VERSION 5.8 ;
BUSBITCHARS "[]" ;
DIVIDERCHAR "/" ;
UNITS
    DATABASE MICRONS 1000 ;
END UNITS

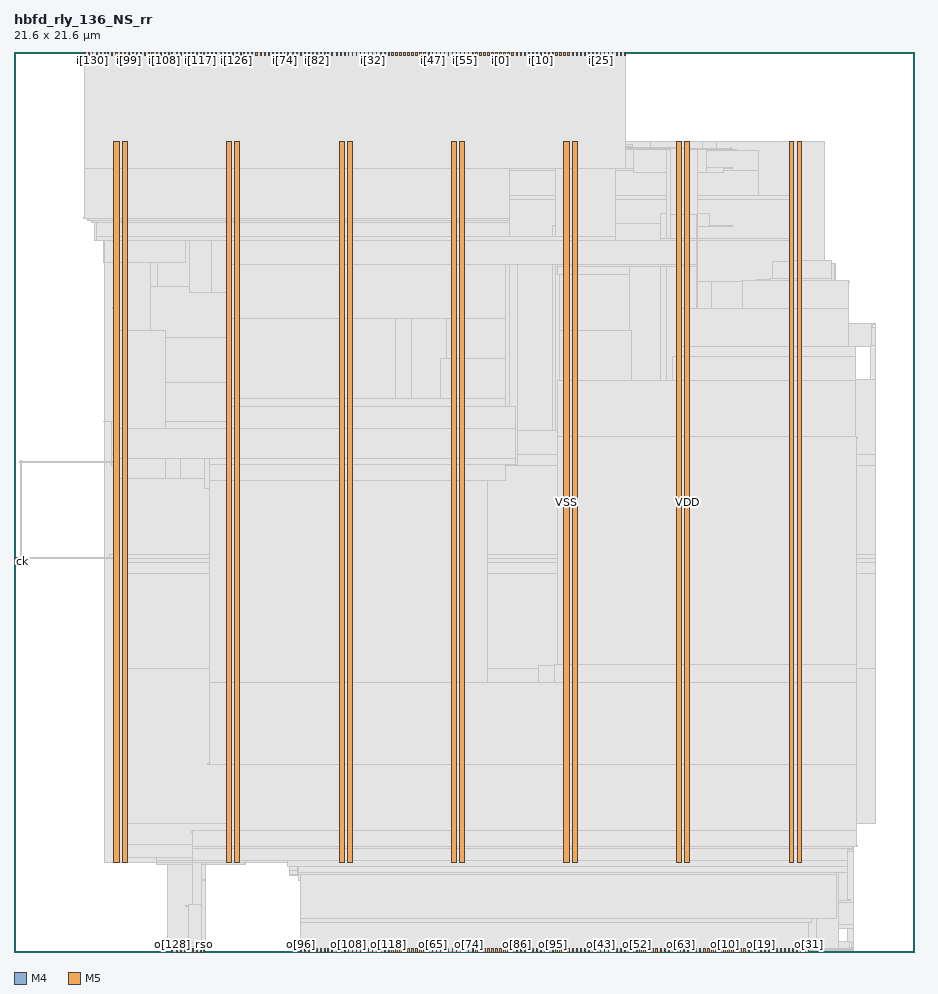
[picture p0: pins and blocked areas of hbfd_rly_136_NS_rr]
MACRO hbfd_rly_136_NS_rr
  FOREIGN hbfd_rly_136_NS_rr 0 0 ;
  CLASS BLOCK ;
  SIZE 21.6 BY 21.6 ;
  PIN ck
    DIRECTION INPUT ;
    USE SIGNAL ;
    PORT
      LAYER M4 ;
        RECT  0 9.36 0.084 9.384 ;
    END
  END ck
  PIN i[0]
    DIRECTION INPUT ;
    USE SIGNAL ;
    PORT
      LAYER M5 ;
        RECT  11.664 21.516 11.688 21.6 ;
    END
  END i[0]
  PIN i[100]
    DIRECTION INPUT ;
    USE SIGNAL ;
    PORT
      LAYER M5 ;
        RECT  2.832 21.516 2.856 21.6 ;
    END
  END i[100]
  PIN i[101]
    DIRECTION INPUT ;
    USE SIGNAL ;
    PORT
      LAYER M5 ;
        RECT  2.928 21.516 2.952 21.6 ;
    END
  END i[101]
  PIN i[102]
    DIRECTION INPUT ;
    USE SIGNAL ;
    PORT
      LAYER M5 ;
        RECT  3.024 21.516 3.048 21.6 ;
    END
  END i[102]
  PIN i[103]
    DIRECTION INPUT ;
    USE SIGNAL ;
    PORT
      LAYER M5 ;
        RECT  3.12 21.516 3.144 21.6 ;
    END
  END i[103]
  PIN i[104]
    DIRECTION INPUT ;
    USE SIGNAL ;
    PORT
      LAYER M5 ;
        RECT  3.216 21.516 3.24 21.6 ;
    END
  END i[104]
  PIN i[105]
    DIRECTION INPUT ;
    USE SIGNAL ;
    PORT
      LAYER M5 ;
        RECT  3.312 21.516 3.336 21.6 ;
    END
  END i[105]
  PIN i[106]
    DIRECTION INPUT ;
    USE SIGNAL ;
    PORT
      LAYER M5 ;
        RECT  3.408 21.516 3.432 21.6 ;
    END
  END i[106]
  PIN i[107]
    DIRECTION INPUT ;
    USE SIGNAL ;
    PORT
      LAYER M5 ;
        RECT  3.504 21.516 3.528 21.6 ;
    END
  END i[107]
  PIN i[108]
    DIRECTION INPUT ;
    USE SIGNAL ;
    PORT
      LAYER M5 ;
        RECT  3.6 21.516 3.624 21.6 ;
    END
  END i[108]
  PIN i[109]
    DIRECTION INPUT ;
    USE SIGNAL ;
    PORT
      LAYER M5 ;
        RECT  3.696 21.516 3.72 21.6 ;
    END
  END i[109]
  PIN i[10]
    DIRECTION INPUT ;
    USE SIGNAL ;
    PORT
      LAYER M5 ;
        RECT  12.624 21.516 12.648 21.6 ;
    END
  END i[10]
  PIN i[110]
    DIRECTION INPUT ;
    USE SIGNAL ;
    PORT
      LAYER M5 ;
        RECT  3.792 21.516 3.816 21.6 ;
    END
  END i[110]
  PIN i[111]
    DIRECTION INPUT ;
    USE SIGNAL ;
    PORT
      LAYER M5 ;
        RECT  3.888 21.516 3.912 21.6 ;
    END
  END i[111]
  PIN i[112]
    DIRECTION INPUT ;
    USE SIGNAL ;
    PORT
      LAYER M5 ;
        RECT  3.984 21.516 4.008 21.6 ;
    END
  END i[112]
  PIN i[113]
    DIRECTION INPUT ;
    USE SIGNAL ;
    PORT
      LAYER M5 ;
        RECT  4.08 21.516 4.104 21.6 ;
    END
  END i[113]
  PIN i[114]
    DIRECTION INPUT ;
    USE SIGNAL ;
    PORT
      LAYER M5 ;
        RECT  4.176 21.516 4.2 21.6 ;
    END
  END i[114]
  PIN i[115]
    DIRECTION INPUT ;
    USE SIGNAL ;
    PORT
      LAYER M5 ;
        RECT  4.272 21.516 4.296 21.6 ;
    END
  END i[115]
  PIN i[116]
    DIRECTION INPUT ;
    USE SIGNAL ;
    PORT
      LAYER M5 ;
        RECT  4.368 21.516 4.392 21.6 ;
    END
  END i[116]
  PIN i[117]
    DIRECTION INPUT ;
    USE SIGNAL ;
    PORT
      LAYER M5 ;
        RECT  4.464 21.516 4.488 21.6 ;
    END
  END i[117]
  PIN i[118]
    DIRECTION INPUT ;
    USE SIGNAL ;
    PORT
      LAYER M5 ;
        RECT  4.56 21.516 4.584 21.6 ;
    END
  END i[118]
  PIN i[119]
    DIRECTION INPUT ;
    USE SIGNAL ;
    PORT
      LAYER M5 ;
        RECT  4.656 21.516 4.68 21.6 ;
    END
  END i[119]
  PIN i[11]
    DIRECTION INPUT ;
    USE SIGNAL ;
    PORT
      LAYER M5 ;
        RECT  12.72 21.516 12.744 21.6 ;
    END
  END i[11]
  PIN i[120]
    DIRECTION INPUT ;
    USE SIGNAL ;
    PORT
      LAYER M5 ;
        RECT  4.752 21.516 4.776 21.6 ;
    END
  END i[120]
  PIN i[121]
    DIRECTION INPUT ;
    USE SIGNAL ;
    PORT
      LAYER M5 ;
        RECT  4.848 21.516 4.872 21.6 ;
    END
  END i[121]
  PIN i[122]
    DIRECTION INPUT ;
    USE SIGNAL ;
    PORT
      LAYER M5 ;
        RECT  4.944 21.516 4.968 21.6 ;
    END
  END i[122]
  PIN i[123]
    DIRECTION INPUT ;
    USE SIGNAL ;
    PORT
      LAYER M5 ;
        RECT  5.04 21.516 5.064 21.6 ;
    END
  END i[123]
  PIN i[124]
    DIRECTION INPUT ;
    USE SIGNAL ;
    PORT
      LAYER M5 ;
        RECT  5.136 21.516 5.16 21.6 ;
    END
  END i[124]
  PIN i[125]
    DIRECTION INPUT ;
    USE SIGNAL ;
    PORT
      LAYER M5 ;
        RECT  5.232 21.516 5.256 21.6 ;
    END
  END i[125]
  PIN i[126]
    DIRECTION INPUT ;
    USE SIGNAL ;
    PORT
      LAYER M5 ;
        RECT  5.328 21.516 5.352 21.6 ;
    END
  END i[126]
  PIN i[127]
    DIRECTION INPUT ;
    USE SIGNAL ;
    PORT
      LAYER M5 ;
        RECT  5.424 21.516 5.448 21.6 ;
    END
  END i[127]
  PIN i[128]
    DIRECTION INPUT ;
    USE SIGNAL ;
    PORT
      LAYER M5 ;
        RECT  1.68 21.516 1.704 21.6 ;
    END
  END i[128]
  PIN i[129]
    DIRECTION INPUT ;
    USE SIGNAL ;
    PORT
      LAYER M5 ;
        RECT  1.776 21.516 1.8 21.6 ;
    END
  END i[129]
  PIN i[12]
    DIRECTION INPUT ;
    USE SIGNAL ;
    PORT
      LAYER M5 ;
        RECT  12.816 21.516 12.84 21.6 ;
    END
  END i[12]
  PIN i[130]
    DIRECTION INPUT ;
    USE SIGNAL ;
    PORT
      LAYER M5 ;
        RECT  1.872 21.516 1.896 21.6 ;
    END
  END i[130]
  PIN i[131]
    DIRECTION INPUT ;
    USE SIGNAL ;
    PORT
      LAYER M5 ;
        RECT  1.968 21.516 1.992 21.6 ;
    END
  END i[131]
  PIN i[132]
    DIRECTION INPUT ;
    USE SIGNAL ;
    PORT
      LAYER M5 ;
        RECT  2.064 21.516 2.088 21.6 ;
    END
  END i[132]
  PIN i[133]
    DIRECTION INPUT ;
    USE SIGNAL ;
    PORT
      LAYER M5 ;
        RECT  2.16 21.516 2.184 21.6 ;
    END
  END i[133]
  PIN i[134]
    DIRECTION INPUT ;
    USE SIGNAL ;
    PORT
      LAYER M5 ;
        RECT  2.256 21.516 2.28 21.6 ;
    END
  END i[134]
  PIN i[135]
    DIRECTION INPUT ;
    USE SIGNAL ;
    PORT
      LAYER M5 ;
        RECT  2.352 21.516 2.376 21.6 ;
    END
  END i[135]
  PIN i[13]
    DIRECTION INPUT ;
    USE SIGNAL ;
    PORT
      LAYER M5 ;
        RECT  12.912 21.516 12.936 21.6 ;
    END
  END i[13]
  PIN i[14]
    DIRECTION INPUT ;
    USE SIGNAL ;
    PORT
      LAYER M5 ;
        RECT  13.008 21.516 13.032 21.6 ;
    END
  END i[14]
  PIN i[15]
    DIRECTION INPUT ;
    USE SIGNAL ;
    PORT
      LAYER M5 ;
        RECT  13.104 21.516 13.128 21.6 ;
    END
  END i[15]
  PIN i[16]
    DIRECTION INPUT ;
    USE SIGNAL ;
    PORT
      LAYER M5 ;
        RECT  13.2 21.516 13.224 21.6 ;
    END
  END i[16]
  PIN i[17]
    DIRECTION INPUT ;
    USE SIGNAL ;
    PORT
      LAYER M5 ;
        RECT  13.296 21.516 13.32 21.6 ;
    END
  END i[17]
  PIN i[18]
    DIRECTION INPUT ;
    USE SIGNAL ;
    PORT
      LAYER M5 ;
        RECT  13.392 21.516 13.416 21.6 ;
    END
  END i[18]
  PIN i[19]
    DIRECTION INPUT ;
    USE SIGNAL ;
    PORT
      LAYER M5 ;
        RECT  13.488 21.516 13.512 21.6 ;
    END
  END i[19]
  PIN i[1]
    DIRECTION INPUT ;
    USE SIGNAL ;
    PORT
      LAYER M5 ;
        RECT  11.76 21.516 11.784 21.6 ;
    END
  END i[1]
  PIN i[20]
    DIRECTION INPUT ;
    USE SIGNAL ;
    PORT
      LAYER M5 ;
        RECT  13.584 21.516 13.608 21.6 ;
    END
  END i[20]
  PIN i[21]
    DIRECTION INPUT ;
    USE SIGNAL ;
    PORT
      LAYER M5 ;
        RECT  13.68 21.516 13.704 21.6 ;
    END
  END i[21]
  PIN i[22]
    DIRECTION INPUT ;
    USE SIGNAL ;
    PORT
      LAYER M5 ;
        RECT  13.776 21.516 13.8 21.6 ;
    END
  END i[22]
  PIN i[23]
    DIRECTION INPUT ;
    USE SIGNAL ;
    PORT
      LAYER M5 ;
        RECT  13.872 21.516 13.896 21.6 ;
    END
  END i[23]
  PIN i[24]
    DIRECTION INPUT ;
    USE SIGNAL ;
    PORT
      LAYER M5 ;
        RECT  13.968 21.516 13.992 21.6 ;
    END
  END i[24]
  PIN i[25]
    DIRECTION INPUT ;
    USE SIGNAL ;
    PORT
      LAYER M5 ;
        RECT  14.064 21.516 14.088 21.6 ;
    END
  END i[25]
  PIN i[26]
    DIRECTION INPUT ;
    USE SIGNAL ;
    PORT
      LAYER M5 ;
        RECT  14.16 21.516 14.184 21.6 ;
    END
  END i[26]
  PIN i[27]
    DIRECTION INPUT ;
    USE SIGNAL ;
    PORT
      LAYER M5 ;
        RECT  14.256 21.516 14.28 21.6 ;
    END
  END i[27]
  PIN i[28]
    DIRECTION INPUT ;
    USE SIGNAL ;
    PORT
      LAYER M5 ;
        RECT  14.352 21.516 14.376 21.6 ;
    END
  END i[28]
  PIN i[29]
    DIRECTION INPUT ;
    USE SIGNAL ;
    PORT
      LAYER M5 ;
        RECT  14.448 21.516 14.472 21.6 ;
    END
  END i[29]
  PIN i[2]
    DIRECTION INPUT ;
    USE SIGNAL ;
    PORT
      LAYER M5 ;
        RECT  11.856 21.516 11.88 21.6 ;
    END
  END i[2]
  PIN i[30]
    DIRECTION INPUT ;
    USE SIGNAL ;
    PORT
      LAYER M5 ;
        RECT  14.544 21.516 14.568 21.6 ;
    END
  END i[30]
  PIN i[31]
    DIRECTION INPUT ;
    USE SIGNAL ;
    PORT
      LAYER M5 ;
        RECT  14.64 21.516 14.664 21.6 ;
    END
  END i[31]
  PIN i[32]
    DIRECTION INPUT ;
    USE SIGNAL ;
    PORT
      LAYER M5 ;
        RECT  8.592 21.516 8.616 21.6 ;
    END
  END i[32]
  PIN i[33]
    DIRECTION INPUT ;
    USE SIGNAL ;
    PORT
      LAYER M5 ;
        RECT  8.688 21.516 8.712 21.6 ;
    END
  END i[33]
  PIN i[34]
    DIRECTION INPUT ;
    USE SIGNAL ;
    PORT
      LAYER M5 ;
        RECT  8.784 21.516 8.808 21.6 ;
    END
  END i[34]
  PIN i[35]
    DIRECTION INPUT ;
    USE SIGNAL ;
    PORT
      LAYER M5 ;
        RECT  8.88 21.516 8.904 21.6 ;
    END
  END i[35]
  PIN i[36]
    DIRECTION INPUT ;
    USE SIGNAL ;
    PORT
      LAYER M5 ;
        RECT  8.976 21.516 9 21.6 ;
    END
  END i[36]
  PIN i[37]
    DIRECTION INPUT ;
    USE SIGNAL ;
    PORT
      LAYER M5 ;
        RECT  9.072 21.516 9.096 21.6 ;
    END
  END i[37]
  PIN i[38]
    DIRECTION INPUT ;
    USE SIGNAL ;
    PORT
      LAYER M5 ;
        RECT  9.168 21.516 9.192 21.6 ;
    END
  END i[38]
  PIN i[39]
    DIRECTION INPUT ;
    USE SIGNAL ;
    PORT
      LAYER M5 ;
        RECT  9.264 21.516 9.288 21.6 ;
    END
  END i[39]
  PIN i[3]
    DIRECTION INPUT ;
    USE SIGNAL ;
    PORT
      LAYER M5 ;
        RECT  11.952 21.516 11.976 21.6 ;
    END
  END i[3]
  PIN i[40]
    DIRECTION INPUT ;
    USE SIGNAL ;
    PORT
      LAYER M5 ;
        RECT  9.36 21.516 9.384 21.6 ;
    END
  END i[40]
  PIN i[41]
    DIRECTION INPUT ;
    USE SIGNAL ;
    PORT
      LAYER M5 ;
        RECT  9.456 21.516 9.48 21.6 ;
    END
  END i[41]
  PIN i[42]
    DIRECTION INPUT ;
    USE SIGNAL ;
    PORT
      LAYER M5 ;
        RECT  9.552 21.516 9.576 21.6 ;
    END
  END i[42]
  PIN i[43]
    DIRECTION INPUT ;
    USE SIGNAL ;
    PORT
      LAYER M5 ;
        RECT  9.648 21.516 9.672 21.6 ;
    END
  END i[43]
  PIN i[44]
    DIRECTION INPUT ;
    USE SIGNAL ;
    PORT
      LAYER M5 ;
        RECT  9.744 21.516 9.768 21.6 ;
    END
  END i[44]
  PIN i[45]
    DIRECTION INPUT ;
    USE SIGNAL ;
    PORT
      LAYER M5 ;
        RECT  9.84 21.516 9.864 21.6 ;
    END
  END i[45]
  PIN i[46]
    DIRECTION INPUT ;
    USE SIGNAL ;
    PORT
      LAYER M5 ;
        RECT  9.936 21.516 9.96 21.6 ;
    END
  END i[46]
  PIN i[47]
    DIRECTION INPUT ;
    USE SIGNAL ;
    PORT
      LAYER M5 ;
        RECT  10.032 21.516 10.056 21.6 ;
    END
  END i[47]
  PIN i[48]
    DIRECTION INPUT ;
    USE SIGNAL ;
    PORT
      LAYER M5 ;
        RECT  10.128 21.516 10.152 21.6 ;
    END
  END i[48]
  PIN i[49]
    DIRECTION INPUT ;
    USE SIGNAL ;
    PORT
      LAYER M5 ;
        RECT  10.224 21.516 10.248 21.6 ;
    END
  END i[49]
  PIN i[4]
    DIRECTION INPUT ;
    USE SIGNAL ;
    PORT
      LAYER M5 ;
        RECT  12.048 21.516 12.072 21.6 ;
    END
  END i[4]
  PIN i[50]
    DIRECTION INPUT ;
    USE SIGNAL ;
    PORT
      LAYER M5 ;
        RECT  10.32 21.516 10.344 21.6 ;
    END
  END i[50]
  PIN i[51]
    DIRECTION INPUT ;
    USE SIGNAL ;
    PORT
      LAYER M5 ;
        RECT  10.416 21.516 10.44 21.6 ;
    END
  END i[51]
  PIN i[52]
    DIRECTION INPUT ;
    USE SIGNAL ;
    PORT
      LAYER M5 ;
        RECT  10.512 21.516 10.536 21.6 ;
    END
  END i[52]
  PIN i[53]
    DIRECTION INPUT ;
    USE SIGNAL ;
    PORT
      LAYER M5 ;
        RECT  10.608 21.516 10.632 21.6 ;
    END
  END i[53]
  PIN i[54]
    DIRECTION INPUT ;
    USE SIGNAL ;
    PORT
      LAYER M5 ;
        RECT  10.704 21.516 10.728 21.6 ;
    END
  END i[54]
  PIN i[55]
    DIRECTION INPUT ;
    USE SIGNAL ;
    PORT
      LAYER M5 ;
        RECT  10.8 21.516 10.824 21.6 ;
    END
  END i[55]
  PIN i[56]
    DIRECTION INPUT ;
    USE SIGNAL ;
    PORT
      LAYER M5 ;
        RECT  10.896 21.516 10.92 21.6 ;
    END
  END i[56]
  PIN i[57]
    DIRECTION INPUT ;
    USE SIGNAL ;
    PORT
      LAYER M5 ;
        RECT  10.992 21.516 11.016 21.6 ;
    END
  END i[57]
  PIN i[58]
    DIRECTION INPUT ;
    USE SIGNAL ;
    PORT
      LAYER M5 ;
        RECT  11.088 21.516 11.112 21.6 ;
    END
  END i[58]
  PIN i[59]
    DIRECTION INPUT ;
    USE SIGNAL ;
    PORT
      LAYER M5 ;
        RECT  11.184 21.516 11.208 21.6 ;
    END
  END i[59]
  PIN i[5]
    DIRECTION INPUT ;
    USE SIGNAL ;
    PORT
      LAYER M5 ;
        RECT  12.144 21.516 12.168 21.6 ;
    END
  END i[5]
  PIN i[60]
    DIRECTION INPUT ;
    USE SIGNAL ;
    PORT
      LAYER M5 ;
        RECT  11.28 21.516 11.304 21.6 ;
    END
  END i[60]
  PIN i[61]
    DIRECTION INPUT ;
    USE SIGNAL ;
    PORT
      LAYER M5 ;
        RECT  11.376 21.516 11.4 21.6 ;
    END
  END i[61]
  PIN i[62]
    DIRECTION INPUT ;
    USE SIGNAL ;
    PORT
      LAYER M5 ;
        RECT  11.472 21.516 11.496 21.6 ;
    END
  END i[62]
  PIN i[63]
    DIRECTION INPUT ;
    USE SIGNAL ;
    PORT
      LAYER M5 ;
        RECT  11.568 21.516 11.592 21.6 ;
    END
  END i[63]
  PIN i[64]
    DIRECTION INPUT ;
    USE SIGNAL ;
    PORT
      LAYER M5 ;
        RECT  5.52 21.516 5.544 21.6 ;
    END
  END i[64]
  PIN i[65]
    DIRECTION INPUT ;
    USE SIGNAL ;
    PORT
      LAYER M5 ;
        RECT  5.616 21.516 5.64 21.6 ;
    END
  END i[65]
  PIN i[66]
    DIRECTION INPUT ;
    USE SIGNAL ;
    PORT
      LAYER M5 ;
        RECT  5.712 21.516 5.736 21.6 ;
    END
  END i[66]
  PIN i[67]
    DIRECTION INPUT ;
    USE SIGNAL ;
    PORT
      LAYER M5 ;
        RECT  5.808 21.516 5.832 21.6 ;
    END
  END i[67]
  PIN i[68]
    DIRECTION INPUT ;
    USE SIGNAL ;
    PORT
      LAYER M5 ;
        RECT  5.904 21.516 5.928 21.6 ;
    END
  END i[68]
  PIN i[69]
    DIRECTION INPUT ;
    USE SIGNAL ;
    PORT
      LAYER M5 ;
        RECT  6 21.516 6.024 21.6 ;
    END
  END i[69]
  PIN i[6]
    DIRECTION INPUT ;
    USE SIGNAL ;
    PORT
      LAYER M5 ;
        RECT  12.24 21.516 12.264 21.6 ;
    END
  END i[6]
  PIN i[70]
    DIRECTION INPUT ;
    USE SIGNAL ;
    PORT
      LAYER M5 ;
        RECT  6.096 21.516 6.12 21.6 ;
    END
  END i[70]
  PIN i[71]
    DIRECTION INPUT ;
    USE SIGNAL ;
    PORT
      LAYER M5 ;
        RECT  6.192 21.516 6.216 21.6 ;
    END
  END i[71]
  PIN i[72]
    DIRECTION INPUT ;
    USE SIGNAL ;
    PORT
      LAYER M5 ;
        RECT  6.288 21.516 6.312 21.6 ;
    END
  END i[72]
  PIN i[73]
    DIRECTION INPUT ;
    USE SIGNAL ;
    PORT
      LAYER M5 ;
        RECT  6.384 21.516 6.408 21.6 ;
    END
  END i[73]
  PIN i[74]
    DIRECTION INPUT ;
    USE SIGNAL ;
    PORT
      LAYER M5 ;
        RECT  6.48 21.516 6.504 21.6 ;
    END
  END i[74]
  PIN i[75]
    DIRECTION INPUT ;
    USE SIGNAL ;
    PORT
      LAYER M5 ;
        RECT  6.576 21.516 6.6 21.6 ;
    END
  END i[75]
  PIN i[76]
    DIRECTION INPUT ;
    USE SIGNAL ;
    PORT
      LAYER M5 ;
        RECT  6.672 21.516 6.696 21.6 ;
    END
  END i[76]
  PIN i[77]
    DIRECTION INPUT ;
    USE SIGNAL ;
    PORT
      LAYER M5 ;
        RECT  6.768 21.516 6.792 21.6 ;
    END
  END i[77]
  PIN i[78]
    DIRECTION INPUT ;
    USE SIGNAL ;
    PORT
      LAYER M5 ;
        RECT  6.864 21.516 6.888 21.6 ;
    END
  END i[78]
  PIN i[79]
    DIRECTION INPUT ;
    USE SIGNAL ;
    PORT
      LAYER M5 ;
        RECT  6.96 21.516 6.984 21.6 ;
    END
  END i[79]
  PIN i[7]
    DIRECTION INPUT ;
    USE SIGNAL ;
    PORT
      LAYER M5 ;
        RECT  12.336 21.516 12.36 21.6 ;
    END
  END i[7]
  PIN i[80]
    DIRECTION INPUT ;
    USE SIGNAL ;
    PORT
      LAYER M5 ;
        RECT  7.056 21.516 7.08 21.6 ;
    END
  END i[80]
  PIN i[81]
    DIRECTION INPUT ;
    USE SIGNAL ;
    PORT
      LAYER M5 ;
        RECT  7.152 21.516 7.176 21.6 ;
    END
  END i[81]
  PIN i[82]
    DIRECTION INPUT ;
    USE SIGNAL ;
    PORT
      LAYER M5 ;
        RECT  7.248 21.516 7.272 21.6 ;
    END
  END i[82]
  PIN i[83]
    DIRECTION INPUT ;
    USE SIGNAL ;
    PORT
      LAYER M5 ;
        RECT  7.344 21.516 7.368 21.6 ;
    END
  END i[83]
  PIN i[84]
    DIRECTION INPUT ;
    USE SIGNAL ;
    PORT
      LAYER M5 ;
        RECT  7.44 21.516 7.464 21.6 ;
    END
  END i[84]
  PIN i[85]
    DIRECTION INPUT ;
    USE SIGNAL ;
    PORT
      LAYER M5 ;
        RECT  7.536 21.516 7.56 21.6 ;
    END
  END i[85]
  PIN i[86]
    DIRECTION INPUT ;
    USE SIGNAL ;
    PORT
      LAYER M5 ;
        RECT  7.632 21.516 7.656 21.6 ;
    END
  END i[86]
  PIN i[87]
    DIRECTION INPUT ;
    USE SIGNAL ;
    PORT
      LAYER M5 ;
        RECT  7.728 21.516 7.752 21.6 ;
    END
  END i[87]
  PIN i[88]
    DIRECTION INPUT ;
    USE SIGNAL ;
    PORT
      LAYER M5 ;
        RECT  7.824 21.516 7.848 21.6 ;
    END
  END i[88]
  PIN i[89]
    DIRECTION INPUT ;
    USE SIGNAL ;
    PORT
      LAYER M5 ;
        RECT  7.92 21.516 7.944 21.6 ;
    END
  END i[89]
  PIN i[8]
    DIRECTION INPUT ;
    USE SIGNAL ;
    PORT
      LAYER M5 ;
        RECT  12.432 21.516 12.456 21.6 ;
    END
  END i[8]
  PIN i[90]
    DIRECTION INPUT ;
    USE SIGNAL ;
    PORT
      LAYER M5 ;
        RECT  8.016 21.516 8.04 21.6 ;
    END
  END i[90]
  PIN i[91]
    DIRECTION INPUT ;
    USE SIGNAL ;
    PORT
      LAYER M5 ;
        RECT  8.112 21.516 8.136 21.6 ;
    END
  END i[91]
  PIN i[92]
    DIRECTION INPUT ;
    USE SIGNAL ;
    PORT
      LAYER M5 ;
        RECT  8.208 21.516 8.232 21.6 ;
    END
  END i[92]
  PIN i[93]
    DIRECTION INPUT ;
    USE SIGNAL ;
    PORT
      LAYER M5 ;
        RECT  8.304 21.516 8.328 21.6 ;
    END
  END i[93]
  PIN i[94]
    DIRECTION INPUT ;
    USE SIGNAL ;
    PORT
      LAYER M5 ;
        RECT  8.4 21.516 8.424 21.6 ;
    END
  END i[94]
  PIN i[95]
    DIRECTION INPUT ;
    USE SIGNAL ;
    PORT
      LAYER M5 ;
        RECT  8.496 21.516 8.52 21.6 ;
    END
  END i[95]
  PIN i[96]
    DIRECTION INPUT ;
    USE SIGNAL ;
    PORT
      LAYER M5 ;
        RECT  2.448 21.516 2.472 21.6 ;
    END
  END i[96]
  PIN i[97]
    DIRECTION INPUT ;
    USE SIGNAL ;
    PORT
      LAYER M5 ;
        RECT  2.544 21.516 2.568 21.6 ;
    END
  END i[97]
  PIN i[98]
    DIRECTION INPUT ;
    USE SIGNAL ;
    PORT
      LAYER M5 ;
        RECT  2.64 21.516 2.664 21.6 ;
    END
  END i[98]
  PIN i[99]
    DIRECTION INPUT ;
    USE SIGNAL ;
    PORT
      LAYER M5 ;
        RECT  2.736 21.516 2.76 21.6 ;
    END
  END i[99]
  PIN i[9]
    DIRECTION INPUT ;
    USE SIGNAL ;
    PORT
      LAYER M5 ;
        RECT  12.528 21.516 12.552 21.6 ;
    END
  END i[9]
  PIN o[0]
    DIRECTION OUTPUT ;
    USE SIGNAL ;
    PORT
      LAYER M5 ;
        RECT  16.08 0 16.104 0.084 ;
    END
  END o[0]
  PIN o[100]
    DIRECTION OUTPUT ;
    USE SIGNAL ;
    PORT
      LAYER M5 ;
        RECT  7.248 0 7.272 0.084 ;
    END
  END o[100]
  PIN o[101]
    DIRECTION OUTPUT ;
    USE SIGNAL ;
    PORT
      LAYER M5 ;
        RECT  7.344 0 7.368 0.084 ;
    END
  END o[101]
  PIN o[102]
    DIRECTION OUTPUT ;
    USE SIGNAL ;
    PORT
      LAYER M5 ;
        RECT  7.44 0 7.464 0.084 ;
    END
  END o[102]
  PIN o[103]
    DIRECTION OUTPUT ;
    USE SIGNAL ;
    PORT
      LAYER M5 ;
        RECT  7.536 0 7.56 0.084 ;
    END
  END o[103]
  PIN o[104]
    DIRECTION OUTPUT ;
    USE SIGNAL ;
    PORT
      LAYER M5 ;
        RECT  7.632 0 7.656 0.084 ;
    END
  END o[104]
  PIN o[105]
    DIRECTION OUTPUT ;
    USE SIGNAL ;
    PORT
      LAYER M5 ;
        RECT  7.728 0 7.752 0.084 ;
    END
  END o[105]
  PIN o[106]
    DIRECTION OUTPUT ;
    USE SIGNAL ;
    PORT
      LAYER M5 ;
        RECT  7.824 0 7.848 0.084 ;
    END
  END o[106]
  PIN o[107]
    DIRECTION OUTPUT ;
    USE SIGNAL ;
    PORT
      LAYER M5 ;
        RECT  7.92 0 7.944 0.084 ;
    END
  END o[107]
  PIN o[108]
    DIRECTION OUTPUT ;
    USE SIGNAL ;
    PORT
      LAYER M5 ;
        RECT  8.016 0 8.04 0.084 ;
    END
  END o[108]
  PIN o[109]
    DIRECTION OUTPUT ;
    USE SIGNAL ;
    PORT
      LAYER M5 ;
        RECT  8.112 0 8.136 0.084 ;
    END
  END o[109]
  PIN o[10]
    DIRECTION OUTPUT ;
    USE SIGNAL ;
    PORT
      LAYER M5 ;
        RECT  17.04 0 17.064 0.084 ;
    END
  END o[10]
  PIN o[110]
    DIRECTION OUTPUT ;
    USE SIGNAL ;
    PORT
      LAYER M5 ;
        RECT  8.208 0 8.232 0.084 ;
    END
  END o[110]
  PIN o[111]
    DIRECTION OUTPUT ;
    USE SIGNAL ;
    PORT
      LAYER M5 ;
        RECT  8.304 0 8.328 0.084 ;
    END
  END o[111]
  PIN o[112]
    DIRECTION OUTPUT ;
    USE SIGNAL ;
    PORT
      LAYER M5 ;
        RECT  8.4 0 8.424 0.084 ;
    END
  END o[112]
  PIN o[113]
    DIRECTION OUTPUT ;
    USE SIGNAL ;
    PORT
      LAYER M5 ;
        RECT  8.496 0 8.52 0.084 ;
    END
  END o[113]
  PIN o[114]
    DIRECTION OUTPUT ;
    USE SIGNAL ;
    PORT
      LAYER M5 ;
        RECT  8.592 0 8.616 0.084 ;
    END
  END o[114]
  PIN o[115]
    DIRECTION OUTPUT ;
    USE SIGNAL ;
    PORT
      LAYER M5 ;
        RECT  8.688 0 8.712 0.084 ;
    END
  END o[115]
  PIN o[116]
    DIRECTION OUTPUT ;
    USE SIGNAL ;
    PORT
      LAYER M5 ;
        RECT  8.784 0 8.808 0.084 ;
    END
  END o[116]
  PIN o[117]
    DIRECTION OUTPUT ;
    USE SIGNAL ;
    PORT
      LAYER M5 ;
        RECT  8.88 0 8.904 0.084 ;
    END
  END o[117]
  PIN o[118]
    DIRECTION OUTPUT ;
    USE SIGNAL ;
    PORT
      LAYER M5 ;
        RECT  8.976 0 9 0.084 ;
    END
  END o[118]
  PIN o[119]
    DIRECTION OUTPUT ;
    USE SIGNAL ;
    PORT
      LAYER M5 ;
        RECT  9.072 0 9.096 0.084 ;
    END
  END o[119]
  PIN o[11]
    DIRECTION OUTPUT ;
    USE SIGNAL ;
    PORT
      LAYER M5 ;
        RECT  17.136 0 17.16 0.084 ;
    END
  END o[11]
  PIN o[120]
    DIRECTION OUTPUT ;
    USE SIGNAL ;
    PORT
      LAYER M5 ;
        RECT  9.168 0 9.192 0.084 ;
    END
  END o[120]
  PIN o[121]
    DIRECTION OUTPUT ;
    USE SIGNAL ;
    PORT
      LAYER M5 ;
        RECT  9.264 0 9.288 0.084 ;
    END
  END o[121]
  PIN o[122]
    DIRECTION OUTPUT ;
    USE SIGNAL ;
    PORT
      LAYER M5 ;
        RECT  9.36 0 9.384 0.084 ;
    END
  END o[122]
  PIN o[123]
    DIRECTION OUTPUT ;
    USE SIGNAL ;
    PORT
      LAYER M5 ;
        RECT  9.456 0 9.48 0.084 ;
    END
  END o[123]
  PIN o[124]
    DIRECTION OUTPUT ;
    USE SIGNAL ;
    PORT
      LAYER M5 ;
        RECT  9.552 0 9.576 0.084 ;
    END
  END o[124]
  PIN o[125]
    DIRECTION OUTPUT ;
    USE SIGNAL ;
    PORT
      LAYER M5 ;
        RECT  9.648 0 9.672 0.084 ;
    END
  END o[125]
  PIN o[126]
    DIRECTION OUTPUT ;
    USE SIGNAL ;
    PORT
      LAYER M5 ;
        RECT  9.744 0 9.768 0.084 ;
    END
  END o[126]
  PIN o[127]
    DIRECTION OUTPUT ;
    USE SIGNAL ;
    PORT
      LAYER M5 ;
        RECT  9.84 0 9.864 0.084 ;
    END
  END o[127]
  PIN o[128]
    DIRECTION OUTPUT ;
    USE SIGNAL ;
    PORT
      LAYER M5 ;
        RECT  3.792 0 3.816 0.084 ;
    END
  END o[128]
  PIN o[129]
    DIRECTION OUTPUT ;
    USE SIGNAL ;
    PORT
      LAYER M5 ;
        RECT  3.888 0 3.912 0.084 ;
    END
  END o[129]
  PIN o[12]
    DIRECTION OUTPUT ;
    USE SIGNAL ;
    PORT
      LAYER M5 ;
        RECT  17.232 0 17.256 0.084 ;
    END
  END o[12]
  PIN o[130]
    DIRECTION OUTPUT ;
    USE SIGNAL ;
    PORT
      LAYER M5 ;
        RECT  3.984 0 4.008 0.084 ;
    END
  END o[130]
  PIN o[131]
    DIRECTION OUTPUT ;
    USE SIGNAL ;
    PORT
      LAYER M5 ;
        RECT  4.08 0 4.104 0.084 ;
    END
  END o[131]
  PIN o[132]
    DIRECTION OUTPUT ;
    USE SIGNAL ;
    PORT
      LAYER M5 ;
        RECT  4.176 0 4.2 0.084 ;
    END
  END o[132]
  PIN o[133]
    DIRECTION OUTPUT ;
    USE SIGNAL ;
    PORT
      LAYER M5 ;
        RECT  4.272 0 4.296 0.084 ;
    END
  END o[133]
  PIN o[134]
    DIRECTION OUTPUT ;
    USE SIGNAL ;
    PORT
      LAYER M5 ;
        RECT  4.368 0 4.392 0.084 ;
    END
  END o[134]
  PIN o[135]
    DIRECTION OUTPUT ;
    USE SIGNAL ;
    PORT
      LAYER M5 ;
        RECT  4.464 0 4.488 0.084 ;
    END
  END o[135]
  PIN o[13]
    DIRECTION OUTPUT ;
    USE SIGNAL ;
    PORT
      LAYER M5 ;
        RECT  17.328 0 17.352 0.084 ;
    END
  END o[13]
  PIN o[14]
    DIRECTION OUTPUT ;
    USE SIGNAL ;
    PORT
      LAYER M5 ;
        RECT  17.424 0 17.448 0.084 ;
    END
  END o[14]
  PIN o[15]
    DIRECTION OUTPUT ;
    USE SIGNAL ;
    PORT
      LAYER M5 ;
        RECT  17.52 0 17.544 0.084 ;
    END
  END o[15]
  PIN o[16]
    DIRECTION OUTPUT ;
    USE SIGNAL ;
    PORT
      LAYER M5 ;
        RECT  17.616 0 17.64 0.084 ;
    END
  END o[16]
  PIN o[17]
    DIRECTION OUTPUT ;
    USE SIGNAL ;
    PORT
      LAYER M5 ;
        RECT  17.712 0 17.736 0.084 ;
    END
  END o[17]
  PIN o[18]
    DIRECTION OUTPUT ;
    USE SIGNAL ;
    PORT
      LAYER M5 ;
        RECT  17.808 0 17.832 0.084 ;
    END
  END o[18]
  PIN o[19]
    DIRECTION OUTPUT ;
    USE SIGNAL ;
    PORT
      LAYER M5 ;
        RECT  17.904 0 17.928 0.084 ;
    END
  END o[19]
  PIN o[1]
    DIRECTION OUTPUT ;
    USE SIGNAL ;
    PORT
      LAYER M5 ;
        RECT  16.176 0 16.2 0.084 ;
    END
  END o[1]
  PIN o[20]
    DIRECTION OUTPUT ;
    USE SIGNAL ;
    PORT
      LAYER M5 ;
        RECT  18 0 18.024 0.084 ;
    END
  END o[20]
  PIN o[21]
    DIRECTION OUTPUT ;
    USE SIGNAL ;
    PORT
      LAYER M5 ;
        RECT  18.096 0 18.12 0.084 ;
    END
  END o[21]
  PIN o[22]
    DIRECTION OUTPUT ;
    USE SIGNAL ;
    PORT
      LAYER M5 ;
        RECT  18.192 0 18.216 0.084 ;
    END
  END o[22]
  PIN o[23]
    DIRECTION OUTPUT ;
    USE SIGNAL ;
    PORT
      LAYER M5 ;
        RECT  18.288 0 18.312 0.084 ;
    END
  END o[23]
  PIN o[24]
    DIRECTION OUTPUT ;
    USE SIGNAL ;
    PORT
      LAYER M5 ;
        RECT  18.384 0 18.408 0.084 ;
    END
  END o[24]
  PIN o[25]
    DIRECTION OUTPUT ;
    USE SIGNAL ;
    PORT
      LAYER M5 ;
        RECT  18.48 0 18.504 0.084 ;
    END
  END o[25]
  PIN o[26]
    DIRECTION OUTPUT ;
    USE SIGNAL ;
    PORT
      LAYER M5 ;
        RECT  18.576 0 18.6 0.084 ;
    END
  END o[26]
  PIN o[27]
    DIRECTION OUTPUT ;
    USE SIGNAL ;
    PORT
      LAYER M5 ;
        RECT  18.672 0 18.696 0.084 ;
    END
  END o[27]
  PIN o[28]
    DIRECTION OUTPUT ;
    USE SIGNAL ;
    PORT
      LAYER M5 ;
        RECT  18.768 0 18.792 0.084 ;
    END
  END o[28]
  PIN o[29]
    DIRECTION OUTPUT ;
    USE SIGNAL ;
    PORT
      LAYER M5 ;
        RECT  18.864 0 18.888 0.084 ;
    END
  END o[29]
  PIN o[2]
    DIRECTION OUTPUT ;
    USE SIGNAL ;
    PORT
      LAYER M5 ;
        RECT  16.272 0 16.296 0.084 ;
    END
  END o[2]
  PIN o[30]
    DIRECTION OUTPUT ;
    USE SIGNAL ;
    PORT
      LAYER M5 ;
        RECT  18.96 0 18.984 0.084 ;
    END
  END o[30]
  PIN o[31]
    DIRECTION OUTPUT ;
    USE SIGNAL ;
    PORT
      LAYER M5 ;
        RECT  19.056 0 19.08 0.084 ;
    END
  END o[31]
  PIN o[32]
    DIRECTION OUTPUT ;
    USE SIGNAL ;
    PORT
      LAYER M5 ;
        RECT  13.008 0 13.032 0.084 ;
    END
  END o[32]
  PIN o[33]
    DIRECTION OUTPUT ;
    USE SIGNAL ;
    PORT
      LAYER M5 ;
        RECT  13.104 0 13.128 0.084 ;
    END
  END o[33]
  PIN o[34]
    DIRECTION OUTPUT ;
    USE SIGNAL ;
    PORT
      LAYER M5 ;
        RECT  13.2 0 13.224 0.084 ;
    END
  END o[34]
  PIN o[35]
    DIRECTION OUTPUT ;
    USE SIGNAL ;
    PORT
      LAYER M5 ;
        RECT  13.296 0 13.32 0.084 ;
    END
  END o[35]
  PIN o[36]
    DIRECTION OUTPUT ;
    USE SIGNAL ;
    PORT
      LAYER M5 ;
        RECT  13.392 0 13.416 0.084 ;
    END
  END o[36]
  PIN o[37]
    DIRECTION OUTPUT ;
    USE SIGNAL ;
    PORT
      LAYER M5 ;
        RECT  13.488 0 13.512 0.084 ;
    END
  END o[37]
  PIN o[38]
    DIRECTION OUTPUT ;
    USE SIGNAL ;
    PORT
      LAYER M5 ;
        RECT  13.584 0 13.608 0.084 ;
    END
  END o[38]
  PIN o[39]
    DIRECTION OUTPUT ;
    USE SIGNAL ;
    PORT
      LAYER M5 ;
        RECT  13.68 0 13.704 0.084 ;
    END
  END o[39]
  PIN o[3]
    DIRECTION OUTPUT ;
    USE SIGNAL ;
    PORT
      LAYER M5 ;
        RECT  16.368 0 16.392 0.084 ;
    END
  END o[3]
  PIN o[40]
    DIRECTION OUTPUT ;
    USE SIGNAL ;
    PORT
      LAYER M5 ;
        RECT  13.776 0 13.8 0.084 ;
    END
  END o[40]
  PIN o[41]
    DIRECTION OUTPUT ;
    USE SIGNAL ;
    PORT
      LAYER M5 ;
        RECT  13.872 0 13.896 0.084 ;
    END
  END o[41]
  PIN o[42]
    DIRECTION OUTPUT ;
    USE SIGNAL ;
    PORT
      LAYER M5 ;
        RECT  13.968 0 13.992 0.084 ;
    END
  END o[42]
  PIN o[43]
    DIRECTION OUTPUT ;
    USE SIGNAL ;
    PORT
      LAYER M5 ;
        RECT  14.064 0 14.088 0.084 ;
    END
  END o[43]
  PIN o[44]
    DIRECTION OUTPUT ;
    USE SIGNAL ;
    PORT
      LAYER M5 ;
        RECT  14.16 0 14.184 0.084 ;
    END
  END o[44]
  PIN o[45]
    DIRECTION OUTPUT ;
    USE SIGNAL ;
    PORT
      LAYER M5 ;
        RECT  14.256 0 14.28 0.084 ;
    END
  END o[45]
  PIN o[46]
    DIRECTION OUTPUT ;
    USE SIGNAL ;
    PORT
      LAYER M5 ;
        RECT  14.352 0 14.376 0.084 ;
    END
  END o[46]
  PIN o[47]
    DIRECTION OUTPUT ;
    USE SIGNAL ;
    PORT
      LAYER M5 ;
        RECT  14.448 0 14.472 0.084 ;
    END
  END o[47]
  PIN o[48]
    DIRECTION OUTPUT ;
    USE SIGNAL ;
    PORT
      LAYER M5 ;
        RECT  14.544 0 14.568 0.084 ;
    END
  END o[48]
  PIN o[49]
    DIRECTION OUTPUT ;
    USE SIGNAL ;
    PORT
      LAYER M5 ;
        RECT  14.64 0 14.664 0.084 ;
    END
  END o[49]
  PIN o[4]
    DIRECTION OUTPUT ;
    USE SIGNAL ;
    PORT
      LAYER M5 ;
        RECT  16.464 0 16.488 0.084 ;
    END
  END o[4]
  PIN o[50]
    DIRECTION OUTPUT ;
    USE SIGNAL ;
    PORT
      LAYER M5 ;
        RECT  14.736 0 14.76 0.084 ;
    END
  END o[50]
  PIN o[51]
    DIRECTION OUTPUT ;
    USE SIGNAL ;
    PORT
      LAYER M5 ;
        RECT  14.832 0 14.856 0.084 ;
    END
  END o[51]
  PIN o[52]
    DIRECTION OUTPUT ;
    USE SIGNAL ;
    PORT
      LAYER M5 ;
        RECT  14.928 0 14.952 0.084 ;
    END
  END o[52]
  PIN o[53]
    DIRECTION OUTPUT ;
    USE SIGNAL ;
    PORT
      LAYER M5 ;
        RECT  15.024 0 15.048 0.084 ;
    END
  END o[53]
  PIN o[54]
    DIRECTION OUTPUT ;
    USE SIGNAL ;
    PORT
      LAYER M5 ;
        RECT  15.12 0 15.144 0.084 ;
    END
  END o[54]
  PIN o[55]
    DIRECTION OUTPUT ;
    USE SIGNAL ;
    PORT
      LAYER M5 ;
        RECT  15.216 0 15.24 0.084 ;
    END
  END o[55]
  PIN o[56]
    DIRECTION OUTPUT ;
    USE SIGNAL ;
    PORT
      LAYER M5 ;
        RECT  15.312 0 15.336 0.084 ;
    END
  END o[56]
  PIN o[57]
    DIRECTION OUTPUT ;
    USE SIGNAL ;
    PORT
      LAYER M5 ;
        RECT  15.408 0 15.432 0.084 ;
    END
  END o[57]
  PIN o[58]
    DIRECTION OUTPUT ;
    USE SIGNAL ;
    PORT
      LAYER M5 ;
        RECT  15.504 0 15.528 0.084 ;
    END
  END o[58]
  PIN o[59]
    DIRECTION OUTPUT ;
    USE SIGNAL ;
    PORT
      LAYER M5 ;
        RECT  15.6 0 15.624 0.084 ;
    END
  END o[59]
  PIN o[5]
    DIRECTION OUTPUT ;
    USE SIGNAL ;
    PORT
      LAYER M5 ;
        RECT  16.56 0 16.584 0.084 ;
    END
  END o[5]
  PIN o[60]
    DIRECTION OUTPUT ;
    USE SIGNAL ;
    PORT
      LAYER M5 ;
        RECT  15.696 0 15.72 0.084 ;
    END
  END o[60]
  PIN o[61]
    DIRECTION OUTPUT ;
    USE SIGNAL ;
    PORT
      LAYER M5 ;
        RECT  15.792 0 15.816 0.084 ;
    END
  END o[61]
  PIN o[62]
    DIRECTION OUTPUT ;
    USE SIGNAL ;
    PORT
      LAYER M5 ;
        RECT  15.888 0 15.912 0.084 ;
    END
  END o[62]
  PIN o[63]
    DIRECTION OUTPUT ;
    USE SIGNAL ;
    PORT
      LAYER M5 ;
        RECT  15.984 0 16.008 0.084 ;
    END
  END o[63]
  PIN o[64]
    DIRECTION OUTPUT ;
    USE SIGNAL ;
    PORT
      LAYER M5 ;
        RECT  9.936 0 9.96 0.084 ;
    END
  END o[64]
  PIN o[65]
    DIRECTION OUTPUT ;
    USE SIGNAL ;
    PORT
      LAYER M5 ;
        RECT  10.032 0 10.056 0.084 ;
    END
  END o[65]
  PIN o[66]
    DIRECTION OUTPUT ;
    USE SIGNAL ;
    PORT
      LAYER M5 ;
        RECT  10.128 0 10.152 0.084 ;
    END
  END o[66]
  PIN o[67]
    DIRECTION OUTPUT ;
    USE SIGNAL ;
    PORT
      LAYER M5 ;
        RECT  10.224 0 10.248 0.084 ;
    END
  END o[67]
  PIN o[68]
    DIRECTION OUTPUT ;
    USE SIGNAL ;
    PORT
      LAYER M5 ;
        RECT  10.32 0 10.344 0.084 ;
    END
  END o[68]
  PIN o[69]
    DIRECTION OUTPUT ;
    USE SIGNAL ;
    PORT
      LAYER M5 ;
        RECT  10.416 0 10.44 0.084 ;
    END
  END o[69]
  PIN o[6]
    DIRECTION OUTPUT ;
    USE SIGNAL ;
    PORT
      LAYER M5 ;
        RECT  16.656 0 16.68 0.084 ;
    END
  END o[6]
  PIN o[70]
    DIRECTION OUTPUT ;
    USE SIGNAL ;
    PORT
      LAYER M5 ;
        RECT  10.512 0 10.536 0.084 ;
    END
  END o[70]
  PIN o[71]
    DIRECTION OUTPUT ;
    USE SIGNAL ;
    PORT
      LAYER M5 ;
        RECT  10.608 0 10.632 0.084 ;
    END
  END o[71]
  PIN o[72]
    DIRECTION OUTPUT ;
    USE SIGNAL ;
    PORT
      LAYER M5 ;
        RECT  10.704 0 10.728 0.084 ;
    END
  END o[72]
  PIN o[73]
    DIRECTION OUTPUT ;
    USE SIGNAL ;
    PORT
      LAYER M5 ;
        RECT  10.8 0 10.824 0.084 ;
    END
  END o[73]
  PIN o[74]
    DIRECTION OUTPUT ;
    USE SIGNAL ;
    PORT
      LAYER M5 ;
        RECT  10.896 0 10.92 0.084 ;
    END
  END o[74]
  PIN o[75]
    DIRECTION OUTPUT ;
    USE SIGNAL ;
    PORT
      LAYER M5 ;
        RECT  10.992 0 11.016 0.084 ;
    END
  END o[75]
  PIN o[76]
    DIRECTION OUTPUT ;
    USE SIGNAL ;
    PORT
      LAYER M5 ;
        RECT  11.088 0 11.112 0.084 ;
    END
  END o[76]
  PIN o[77]
    DIRECTION OUTPUT ;
    USE SIGNAL ;
    PORT
      LAYER M5 ;
        RECT  11.184 0 11.208 0.084 ;
    END
  END o[77]
  PIN o[78]
    DIRECTION OUTPUT ;
    USE SIGNAL ;
    PORT
      LAYER M5 ;
        RECT  11.28 0 11.304 0.084 ;
    END
  END o[78]
  PIN o[79]
    DIRECTION OUTPUT ;
    USE SIGNAL ;
    PORT
      LAYER M5 ;
        RECT  11.376 0 11.4 0.084 ;
    END
  END o[79]
  PIN o[7]
    DIRECTION OUTPUT ;
    USE SIGNAL ;
    PORT
      LAYER M5 ;
        RECT  16.752 0 16.776 0.084 ;
    END
  END o[7]
  PIN o[80]
    DIRECTION OUTPUT ;
    USE SIGNAL ;
    PORT
      LAYER M5 ;
        RECT  11.472 0 11.496 0.084 ;
    END
  END o[80]
  PIN o[81]
    DIRECTION OUTPUT ;
    USE SIGNAL ;
    PORT
      LAYER M5 ;
        RECT  11.568 0 11.592 0.084 ;
    END
  END o[81]
  PIN o[82]
    DIRECTION OUTPUT ;
    USE SIGNAL ;
    PORT
      LAYER M5 ;
        RECT  11.664 0 11.688 0.084 ;
    END
  END o[82]
  PIN o[83]
    DIRECTION OUTPUT ;
    USE SIGNAL ;
    PORT
      LAYER M5 ;
        RECT  11.76 0 11.784 0.084 ;
    END
  END o[83]
  PIN o[84]
    DIRECTION OUTPUT ;
    USE SIGNAL ;
    PORT
      LAYER M5 ;
        RECT  11.856 0 11.88 0.084 ;
    END
  END o[84]
  PIN o[85]
    DIRECTION OUTPUT ;
    USE SIGNAL ;
    PORT
      LAYER M5 ;
        RECT  11.952 0 11.976 0.084 ;
    END
  END o[85]
  PIN o[86]
    DIRECTION OUTPUT ;
    USE SIGNAL ;
    PORT
      LAYER M5 ;
        RECT  12.048 0 12.072 0.084 ;
    END
  END o[86]
  PIN o[87]
    DIRECTION OUTPUT ;
    USE SIGNAL ;
    PORT
      LAYER M5 ;
        RECT  12.144 0 12.168 0.084 ;
    END
  END o[87]
  PIN o[88]
    DIRECTION OUTPUT ;
    USE SIGNAL ;
    PORT
      LAYER M5 ;
        RECT  12.24 0 12.264 0.084 ;
    END
  END o[88]
  PIN o[89]
    DIRECTION OUTPUT ;
    USE SIGNAL ;
    PORT
      LAYER M5 ;
        RECT  12.336 0 12.36 0.084 ;
    END
  END o[89]
  PIN o[8]
    DIRECTION OUTPUT ;
    USE SIGNAL ;
    PORT
      LAYER M5 ;
        RECT  16.848 0 16.872 0.084 ;
    END
  END o[8]
  PIN o[90]
    DIRECTION OUTPUT ;
    USE SIGNAL ;
    PORT
      LAYER M5 ;
        RECT  12.432 0 12.456 0.084 ;
    END
  END o[90]
  PIN o[91]
    DIRECTION OUTPUT ;
    USE SIGNAL ;
    PORT
      LAYER M5 ;
        RECT  12.528 0 12.552 0.084 ;
    END
  END o[91]
  PIN o[92]
    DIRECTION OUTPUT ;
    USE SIGNAL ;
    PORT
      LAYER M5 ;
        RECT  12.624 0 12.648 0.084 ;
    END
  END o[92]
  PIN o[93]
    DIRECTION OUTPUT ;
    USE SIGNAL ;
    PORT
      LAYER M5 ;
        RECT  12.72 0 12.744 0.084 ;
    END
  END o[93]
  PIN o[94]
    DIRECTION OUTPUT ;
    USE SIGNAL ;
    PORT
      LAYER M5 ;
        RECT  12.816 0 12.84 0.084 ;
    END
  END o[94]
  PIN o[95]
    DIRECTION OUTPUT ;
    USE SIGNAL ;
    PORT
      LAYER M5 ;
        RECT  12.912 0 12.936 0.084 ;
    END
  END o[95]
  PIN o[96]
    DIRECTION OUTPUT ;
    USE SIGNAL ;
    PORT
      LAYER M5 ;
        RECT  6.864 0 6.888 0.084 ;
    END
  END o[96]
  PIN o[97]
    DIRECTION OUTPUT ;
    USE SIGNAL ;
    PORT
      LAYER M5 ;
        RECT  6.96 0 6.984 0.084 ;
    END
  END o[97]
  PIN o[98]
    DIRECTION OUTPUT ;
    USE SIGNAL ;
    PORT
      LAYER M5 ;
        RECT  7.056 0 7.08 0.084 ;
    END
  END o[98]
  PIN o[99]
    DIRECTION OUTPUT ;
    USE SIGNAL ;
    PORT
      LAYER M5 ;
        RECT  7.152 0 7.176 0.084 ;
    END
  END o[99]
  PIN o[9]
    DIRECTION OUTPUT ;
    USE SIGNAL ;
    PORT
      LAYER M5 ;
        RECT  16.944 0 16.968 0.084 ;
    END
  END o[9]
  PIN rs
    DIRECTION INPUT ;
    USE SIGNAL ;
    PORT
      LAYER M4 ;
        RECT  0 9.456 0.084 9.48 ;
    END
  END rs
  PIN rso
    DIRECTION OUTPUT ;
    USE SIGNAL ;
    PORT
      LAYER M5 ;
        RECT  4.56 0 4.584 0.084 ;
    END
  END rso
  PIN VDD
    DIRECTION INOUT ;
    USE POWER ;
    PORT
      LAYER M5 ;
        RECT  18.792 2.151 18.912 19.449 ;
        RECT  16.092 2.151 16.212 19.449 ;
        RECT  13.392 2.151 13.512 19.449 ;
        RECT  10.692 2.151 10.812 19.449 ;
        RECT  7.992 2.151 8.112 19.449 ;
        RECT  5.292 2.151 5.412 19.449 ;
        RECT  2.592 2.151 2.712 19.449 ;
    END
  END VDD
  PIN VSS
    DIRECTION INOUT ;
    USE GROUND ;
    PORT
      LAYER M5 ;
        RECT  18.6 2.137 18.72 19.463 ;
        RECT  15.9 2.137 16.02 19.463 ;
        RECT  13.2 2.137 13.32 19.463 ;
        RECT  10.5 2.137 10.62 19.463 ;
        RECT  7.8 2.137 7.92 19.463 ;
        RECT  5.1 2.137 5.22 19.463 ;
        RECT  2.4 2.137 2.52 19.463 ;
    END
  END VSS
  OBS
    LAYER RVTN ;
     RECT  2.16 2.16 19.44 2.295 ;
     RECT  2.16 2.565 19.44 2.835 ;
     RECT  2.16 3.105 19.44 3.375 ;
     RECT  2.16 3.645 19.44 3.915 ;
     RECT  2.16 4.185 19.44 4.455 ;
     RECT  2.16 4.725 19.44 4.995 ;
     RECT  2.16 5.265 19.44 5.535 ;
     RECT  2.16 5.805 19.44 6.075 ;
     RECT  2.16 6.345 19.44 6.615 ;
     RECT  2.16 6.885 19.44 7.155 ;
     RECT  2.16 7.425 19.44 7.695 ;
     RECT  2.16 7.965 19.44 8.235 ;
     RECT  2.16 8.505 19.44 8.775 ;
     RECT  2.16 9.045 19.44 9.315 ;
     RECT  2.16 9.585 19.44 9.855 ;
     RECT  2.16 10.125 19.44 10.395 ;
     RECT  2.16 10.665 19.44 10.935 ;
     RECT  2.16 11.205 19.44 11.475 ;
     RECT  2.16 11.745 19.44 12.015 ;
     RECT  2.16 12.285 19.44 12.555 ;
     RECT  2.16 12.825 19.44 13.095 ;
     RECT  2.16 13.365 19.44 13.635 ;
     RECT  2.16 13.905 19.44 14.175 ;
     RECT  2.16 14.445 19.44 14.715 ;
     RECT  2.16 14.985 19.44 15.255 ;
     RECT  2.16 15.525 19.44 15.795 ;
     RECT  2.16 16.065 19.44 16.335 ;
     RECT  2.16 16.605 19.44 16.875 ;
     RECT  2.16 17.145 19.44 17.415 ;
     RECT  2.16 17.685 19.44 17.955 ;
     RECT  2.16 18.225 19.44 18.495 ;
     RECT  2.16 18.765 19.44 19.035 ;
     RECT  2.16 19.305 19.44 19.44 ;
    LAYER RVTP ;
     RECT  2.16 2.295 19.44 2.565 ;
     RECT  2.16 2.835 19.44 3.105 ;
     RECT  2.16 3.375 19.44 3.645 ;
     RECT  2.16 3.915 19.44 4.185 ;
     RECT  2.16 4.455 19.44 4.725 ;
     RECT  2.16 4.995 19.44 5.265 ;
     RECT  2.16 5.535 19.44 5.805 ;
     RECT  2.16 6.075 19.44 6.345 ;
     RECT  2.16 6.615 19.44 6.885 ;
     RECT  2.16 7.155 19.44 7.425 ;
     RECT  2.16 7.695 19.44 7.965 ;
     RECT  2.16 8.235 19.44 8.505 ;
     RECT  2.16 8.775 19.44 9.045 ;
     RECT  2.16 9.315 19.44 9.585 ;
     RECT  2.16 9.855 19.44 10.125 ;
     RECT  2.16 10.395 19.44 10.665 ;
     RECT  2.16 10.935 19.44 11.205 ;
     RECT  2.16 11.475 19.44 11.745 ;
     RECT  2.16 12.015 19.44 12.285 ;
     RECT  2.16 12.555 19.44 12.825 ;
     RECT  2.16 13.095 19.44 13.365 ;
     RECT  2.16 13.635 19.44 13.905 ;
     RECT  2.16 14.175 19.44 14.445 ;
     RECT  2.16 14.715 19.44 14.985 ;
     RECT  2.16 15.255 19.44 15.525 ;
     RECT  2.16 15.795 19.44 16.065 ;
     RECT  2.16 16.335 19.44 16.605 ;
     RECT  2.16 16.875 19.44 17.145 ;
     RECT  2.16 17.415 19.44 17.685 ;
     RECT  2.16 17.955 19.44 18.225 ;
     RECT  2.16 18.495 19.44 18.765 ;
     RECT  2.16 19.035 19.44 19.305 ;
    LAYER M1 ;
     RECT  2.16 2.151 19.44 19.449 ;
    LAYER M2 ;
     RECT  2.155 12.726 2.16 12.744 ;
     RECT  1.975 17.082 2.16 17.1 ;
     RECT  2.155 18.036 2.16 18.054 ;
     RECT  2.16 2.151 3.415 19.449 ;
     RECT  3.415 2.106 5.567 19.449 ;
     RECT  5.567 2.151 6.619 19.449 ;
     RECT  6.619 1.836 12.803 19.449 ;
     RECT  12.803 2.106 13.379 19.449 ;
     RECT  13.379 2.151 14.539 19.449 ;
     RECT  14.539 2.106 15.287 19.449 ;
     RECT  15.287 2.151 16.519 19.449 ;
     RECT  16.519 2.106 16.871 19.449 ;
     RECT  16.871 2.151 19.44 19.449 ;
     RECT  19.44 2.61 19.499 4.482 ;
     RECT  19.44 6.084 19.499 6.984 ;
     RECT  19.44 11.916 19.499 11.934 ;
     RECT  19.44 14.526 19.715 16.524 ;
     RECT  19.499 2.646 19.751 4.482 ;
     RECT  19.715 14.526 19.751 15.786 ;
     RECT  19.751 2.844 19.823 4.482 ;
     RECT  19.44 9.09 19.823 9.108 ;
     RECT  19.823 3.078 19.967 4.482 ;
     RECT  19.44 13.572 19.967 13.734 ;
     RECT  19.967 3.078 20.003 4.14 ;
     RECT  19.499 6.156 20.039 6.984 ;
     RECT  20.039 6.354 20.075 6.984 ;
     RECT  20.075 6.516 20.111 6.984 ;
     RECT  18.679 0.036 20.147 0.054 ;
     RECT  20.111 6.516 20.147 6.534 ;
     RECT  19.751 14.526 20.579 15.084 ;
     RECT  20.003 3.078 20.615 3.708 ;
     RECT  20.579 14.958 20.615 15.084 ;
     RECT  20.615 3.078 20.651 3.366 ;
     RECT  19.967 13.572 20.651 13.59 ;
     RECT  20.651 3.078 20.687 3.096 ;
     RECT  20.615 15.066 20.687 15.084 ;
    LAYER M3 ;
     RECT  18.684 0.031 18.702 0.091 ;
     RECT  20.124 0.031 20.142 0.091 ;
     RECT  18.684 0.091 18.81 0.125 ;
     RECT  10.188 0.091 10.206 0.221 ;
     RECT  13.896 0.091 13.914 0.221 ;
     RECT  16.02 0.091 16.398 0.221 ;
     RECT  20.088 0.091 20.142 0.235 ;
     RECT  18.792 0.125 18.81 0.317 ;
     RECT  20.016 0.235 20.142 0.571 ;
     RECT  8.136 0.571 8.154 0.619 ;
     RECT  19.62 0.571 20.142 0.667 ;
     RECT  15.228 0.763 15.246 0.941 ;
     RECT  7.02 0.091 7.29 1.147 ;
     RECT  16.38 0.221 16.398 1.147 ;
     RECT  19.584 0.667 20.142 1.195 ;
     RECT  16.38 1.147 17.154 1.277 ;
     RECT  16.38 1.277 16.686 1.325 ;
     RECT  6.876 1.147 7.29 1.723 ;
     RECT  8.136 0.619 8.298 1.723 ;
     RECT  18.36 1.243 18.378 1.723 ;
     RECT  13.644 1.723 13.662 1.819 ;
     RECT  6.84 1.723 8.694 1.831 ;
     RECT  6.624 1.831 8.694 1.867 ;
     RECT  10.836 1.723 10.854 1.876 ;
     RECT  13.608 1.819 13.662 1.915 ;
     RECT  16.38 1.325 16.398 1.915 ;
     RECT  6.624 1.867 9.018 1.957 ;
     RECT  10.368 1.876 10.854 1.963 ;
     RECT  13.572 1.915 13.662 2.011 ;
     RECT  6.624 1.957 9.522 2.065 ;
     RECT  10.368 1.963 11.07 2.065 ;
     RECT  3.672 0.091 4.59 2.101 ;
     RECT  12.78 1.831 12.798 2.101 ;
     RECT  13.536 2.011 13.662 2.101 ;
     RECT  15.732 1.915 16.398 2.101 ;
     RECT  3.42 2.101 4.59 2.143 ;
     RECT  5.544 2.101 5.562 2.143 ;
     RECT  18.036 1.723 18.378 2.143 ;
     RECT  14.544 2.101 16.866 2.155 ;
     RECT  18.036 2.143 18.705 2.155 ;
     RECT  3.42 2.143 5.562 2.191 ;
     RECT  6.624 2.065 11.07 2.191 ;
     RECT  11.916 2.065 11.934 2.191 ;
     RECT  18.036 2.155 18.81 2.191 ;
     RECT  14.544 2.155 16.938 2.251 ;
     RECT  2.415 2.143 2.505 2.263 ;
     RECT  3.42 2.191 5.886 2.263 ;
     RECT  12.78 2.101 13.662 2.263 ;
     RECT  14.544 2.251 17.046 2.263 ;
     RECT  12.78 2.263 17.046 2.371 ;
     RECT  17.892 2.191 18.81 2.371 ;
     RECT  12.78 2.371 18.81 2.413 ;
     RECT  19.548 1.195 20.142 2.413 ;
     RECT  6.624 2.191 11.934 2.461 ;
     RECT  12.78 2.413 20.142 2.461 ;
     RECT  2.415 2.263 5.886 2.569 ;
     RECT  6.624 2.461 20.142 2.569 ;
     RECT  2.415 2.569 20.142 3.073 ;
     RECT  2.415 3.073 20.682 6.809 ;
     RECT  2.415 6.809 18.897 9.085 ;
     RECT  19.692 6.809 20.682 9.085 ;
     RECT  2.415 9.085 20.682 9.355 ;
     RECT  2.412 9.355 20.682 9.451 ;
     RECT  2.304 9.451 20.682 9.545 ;
     RECT  2.415 9.545 20.682 11.677 ;
     RECT  2.34 11.677 20.682 11.939 ;
     RECT  2.34 11.939 18.897 12.721 ;
     RECT  19.692 11.939 20.682 13.739 ;
     RECT  20.556 13.739 20.682 14.549 ;
     RECT  20.592 14.549 20.682 14.981 ;
     RECT  20.664 14.981 20.682 15.089 ;
     RECT  19.692 13.739 19.746 15.791 ;
     RECT  19.692 15.791 19.71 16.529 ;
     RECT  2.16 12.721 18.897 17.077 ;
     RECT  1.98 17.077 18.897 17.117 ;
     RECT  2.16 17.117 18.897 18.059 ;
     RECT  2.196 18.059 18.897 18.149 ;
     RECT  2.196 18.149 17.874 18.761 ;
     RECT  18.615 18.149 18.897 19.187 ;
     RECT  2.268 18.761 17.874 19.229 ;
     RECT  2.268 19.229 17.334 19.265 ;
     RECT  2.268 19.265 17.226 19.277 ;
     RECT  2.268 19.277 16.074 19.301 ;
     RECT  17.208 19.277 17.226 19.301 ;
     RECT  2.415 19.301 14.85 19.325 ;
     RECT  2.415 19.325 3.546 19.373 ;
     RECT  4.392 19.325 14.85 19.373 ;
     RECT  9.864 19.373 12.294 19.379 ;
     RECT  5.115 19.373 6.318 19.421 ;
     RECT  7.815 19.373 8.586 19.421 ;
     RECT  13.215 19.373 14.202 19.421 ;
     RECT  2.415 19.373 3.294 19.457 ;
     RECT  5.115 19.421 6.21 19.457 ;
     RECT  7.815 19.421 8.154 19.457 ;
     RECT  13.215 19.421 13.878 19.457 ;
     RECT  15.915 19.301 16.005 19.457 ;
     RECT  18.615 19.187 18.705 19.457 ;
     RECT  2.736 19.457 3.294 19.565 ;
     RECT  5.616 19.457 6.21 19.565 ;
     RECT  2.916 19.565 3.294 19.613 ;
     RECT  8.136 19.457 8.154 19.613 ;
     RECT  9.864 19.379 11.43 19.613 ;
     RECT  13.356 19.457 13.878 19.661 ;
     RECT  2.952 19.613 3.294 19.949 ;
     RECT  12.276 19.379 12.294 19.997 ;
     RECT  5.724 19.565 6.21 20.573 ;
     RECT  10.836 19.613 11.43 21.245 ;
     RECT  2.952 19.949 2.97 21.341 ;
     RECT  2.376 21.355 2.394 21.485 ;
     RECT  6.192 20.573 6.21 21.485 ;
     RECT  9.864 19.613 9.882 21.485 ;
     RECT  10.836 21.245 11.394 21.485 ;
     RECT  13.86 19.661 13.878 21.485 ;
    LAYER M4 ;
     RECT  0.06 9.36 0.179 9.48 ;
     RECT  1.669 17.616 1.765 17.64 ;
     RECT  1.765 17.568 1.861 17.64 ;
     RECT  1.861 17.52 1.925 17.64 ;
     RECT  1.925 17.088 2.149 17.64 ;
     RECT  2.293 21.36 2.321 21.384 ;
     RECT  0.179 9.456 2.408 9.48 ;
     RECT  0.133 11.76 2.408 11.784 ;
     RECT  2.401 14.4 2.408 14.424 ;
     RECT  2.365 15.456 2.408 15.48 ;
     RECT  2.149 16.56 2.408 17.64 ;
     RECT  2.321 21.36 2.438 21.48 ;
     RECT  2.408 2.148 2.512 19.452 ;
     RECT  2.512 2.418 2.533 19.452 ;
     RECT  2.533 2.418 2.704 19.608 ;
     RECT  2.438 21.36 2.725 21.432 ;
     RECT  2.704 13.68 2.819 19.608 ;
     RECT  2.725 21.312 2.819 21.432 ;
     RECT  2.819 21.312 2.981 21.336 ;
     RECT  2.819 15.984 3.265 19.608 ;
     RECT  3.265 15.984 3.436 19.944 ;
     RECT  3.436 18.144 3.443 19.944 ;
     RECT  2.819 13.68 3.635 14.904 ;
     RECT  3.661 0.096 3.949 0.12 ;
     RECT  2.704 11.376 3.985 12.504 ;
     RECT  3.949 0.096 4.033 0.216 ;
     RECT  3.436 15.984 4.201 17.112 ;
     RECT  4.124 1.104 4.211 1.128 ;
     RECT  4.357 1.152 4.453 1.176 ;
     RECT  3.443 18.144 4.453 19.368 ;
     RECT  4.453 1.152 4.493 1.752 ;
     RECT  3.985 11.376 4.561 12.552 ;
     RECT  4.493 1.728 4.565 1.752 ;
     RECT  4.033 0.096 4.601 0.12 ;
     RECT  4.201 15.84 4.741 17.112 ;
     RECT  4.453 18.096 4.741 19.368 ;
     RECT  4.561 11.136 4.981 12.552 ;
     RECT  4.261 2.88 5.108 2.904 ;
     RECT  4.652 4.512 5.108 4.536 ;
     RECT  4.94 6.24 5.108 6.264 ;
     RECT  4.981 7.344 5.108 7.368 ;
     RECT  4.981 10.32 5.108 12.552 ;
     RECT  3.635 13.68 5.108 14.76 ;
     RECT  4.741 15.84 5.108 19.368 ;
     RECT  4.885 21.408 5.125 21.432 ;
     RECT  5.108 2.148 5.212 19.452 ;
     RECT  5.125 21.408 5.221 21.48 ;
     RECT  5.221 21.168 5.317 21.48 ;
     RECT  5.212 2.208 5.404 19.452 ;
     RECT  5.317 21.072 5.413 21.48 ;
     RECT  5.404 10.272 5.461 19.452 ;
     RECT  5.461 10.272 5.645 19.56 ;
     RECT  5.645 10.272 5.681 19.416 ;
     RECT  5.413 20.976 5.713 21.48 ;
     RECT  5.681 10.272 5.825 15.528 ;
     RECT  5.713 20.544 5.843 21.48 ;
     RECT  5.825 10.272 5.869 15.432 ;
     RECT  5.869 10.608 6.041 15.432 ;
     RECT  5.404 8.544 6.085 8.568 ;
     RECT  5.843 21.456 6.221 21.48 ;
     RECT  5.681 16.512 6.257 19.416 ;
     RECT  6.041 10.8 6.329 15.432 ;
     RECT  6.257 18.096 6.419 19.416 ;
     RECT  5.404 2.208 6.565 2.28 ;
     RECT  6.565 2.064 6.613 2.28 ;
     RECT  6.613 2.064 6.709 2.52 ;
     RECT  6.661 3.936 6.709 3.96 ;
     RECT  6.257 16.512 6.793 16.824 ;
     RECT  6.709 2.064 6.805 3.96 ;
     RECT  6.805 1.872 6.829 3.96 ;
     RECT  6.829 1.728 6.865 3.96 ;
     RECT  7.045 9.744 7.109 9.768 ;
     RECT  6.805 5.568 7.189 5.592 ;
     RECT  7.109 9.696 7.285 9.768 ;
     RECT  6.329 10.8 7.285 15 ;
     RECT  6.949 0.096 7.301 0.12 ;
     RECT  6.793 15.984 7.333 16.824 ;
     RECT  6.865 1.152 7.381 3.96 ;
     RECT  7.189 5.136 7.381 5.592 ;
     RECT  7.285 9.696 7.429 15 ;
     RECT  7.333 15.984 7.429 17.064 ;
     RECT  7.477 0.144 7.669 0.168 ;
     RECT  7.381 1.152 7.669 5.592 ;
     RECT  7.477 21.408 7.669 21.432 ;
     RECT  7.669 21.312 7.763 21.432 ;
     RECT  7.429 9.696 7.801 17.064 ;
     RECT  6.419 18.096 7.801 19.368 ;
     RECT  7.669 0.144 7.808 5.592 ;
     RECT  7.801 9.696 7.808 19.368 ;
     RECT  7.808 0.144 7.813 19.452 ;
     RECT  7.763 21.312 8.005 21.384 ;
     RECT  8.005 21.216 8.101 21.384 ;
     RECT  7.813 0.144 8.104 19.608 ;
     RECT  8.104 18.816 8.165 19.608 ;
     RECT  8.101 21.12 8.291 21.384 ;
     RECT  8.104 0.144 8.339 5.592 ;
     RECT  8.104 10.944 8.381 17.832 ;
     RECT  8.291 21.36 8.387 21.384 ;
     RECT  8.104 7.44 8.489 7.464 ;
     RECT  8.165 18.816 8.723 19.416 ;
     RECT  8.339 1.728 8.749 5.592 ;
     RECT  8.749 1.872 9.029 5.592 ;
     RECT  8.381 16.416 9.071 17.832 ;
     RECT  8.723 18.816 9.071 19.368 ;
     RECT  9.029 1.968 9.397 5.592 ;
     RECT  8.381 10.944 9.541 15.432 ;
     RECT  9.071 16.416 9.541 19.368 ;
     RECT  8.339 0.144 9.925 0.264 ;
     RECT  9.397 1.968 10.165 6.312 ;
     RECT  9.925 0.096 10.217 0.264 ;
     RECT  9.809 21.456 10.261 21.48 ;
     RECT  10.165 1.68 10.357 6.312 ;
     RECT  9.541 10.944 10.465 19.368 ;
     RECT  10.357 1.152 10.508 6.312 ;
     RECT  10.465 10.944 10.508 19.608 ;
     RECT  10.508 1.152 10.547 19.608 ;
     RECT  10.547 1.728 10.549 19.608 ;
     RECT  10.549 1.728 10.804 19.56 ;
     RECT  10.804 11.328 10.835 19.56 ;
     RECT  10.804 1.728 10.865 6.312 ;
     RECT  10.261 21.168 10.969 21.48 ;
     RECT  10.217 0.144 10.979 0.168 ;
     RECT  10.865 1.968 11.081 6.312 ;
     RECT  10.969 20.544 11.405 21.48 ;
     RECT  11.405 20.544 11.411 21.288 ;
     RECT  10.835 11.328 11.699 19.368 ;
     RECT  11.699 11.328 11.795 17.64 ;
     RECT  11.699 18.72 11.795 19.368 ;
     RECT  11.411 20.544 11.795 21.24 ;
     RECT  11.795 11.424 11.801 17.64 ;
     RECT  11.801 11.712 11.891 17.64 ;
     RECT  11.891 11.712 12.076 17.16 ;
     RECT  11.795 21.216 12.179 21.24 ;
     RECT  11.081 2.496 12.229 6.312 ;
     RECT  11.795 18.816 12.265 19.368 ;
     RECT  12.229 2.496 12.589 6.456 ;
     RECT  12.265 18.816 12.659 19.992 ;
     RECT  12.076 12.528 12.913 17.16 ;
     RECT  12.913 12.528 12.997 17.448 ;
     RECT  12.659 18.816 12.997 19.656 ;
     RECT  12.589 2.496 13.093 6.888 ;
     RECT  13.093 1.728 13.208 6.888 ;
     RECT  12.997 12.528 13.208 19.656 ;
     RECT  13.285 0.336 13.381 0.36 ;
     RECT  13.208 1.728 13.385 19.656 ;
     RECT  13.381 0.336 13.429 0.456 ;
     RECT  13.385 1.728 13.504 19.608 ;
     RECT  13.477 21.312 13.573 21.336 ;
     RECT  13.429 0.144 13.619 0.456 ;
     RECT  13.573 21.312 13.619 21.48 ;
     RECT  13.619 0.144 13.667 0.36 ;
     RECT  13.504 18.72 13.667 19.608 ;
     RECT  13.504 1.728 13.673 6.888 ;
     RECT  13.667 18.816 13.673 19.608 ;
     RECT  13.504 12 13.715 17.496 ;
     RECT  13.667 0.144 13.858 0.216 ;
     RECT  13.619 21.456 13.889 21.48 ;
     RECT  13.858 0.096 14.195 0.216 ;
     RECT  13.673 18.816 14.213 19.416 ;
     RECT  13.504 9.072 14.243 9.096 ;
     RECT  13.673 2.304 14.537 6.888 ;
     RECT  14.213 18.816 14.609 19.368 ;
     RECT  14.537 2.304 14.641 6.36 ;
     RECT  14.609 18.816 14.681 19.32 ;
     RECT  14.681 18.816 14.857 19.272 ;
     RECT  14.641 2.256 15.061 6.36 ;
     RECT  14.821 0.336 15.173 0.36 ;
     RECT  15.173 0.336 15.212 0.792 ;
     RECT  15.212 0.336 15.397 0.936 ;
     RECT  15.061 2.208 15.397 6.36 ;
     RECT  13.715 12.336 15.505 17.496 ;
     RECT  15.505 12.336 15.649 17.736 ;
     RECT  14.857 18.72 15.649 19.272 ;
     RECT  15.397 0.336 15.733 6.36 ;
     RECT  15.733 0.192 15.781 6.6 ;
     RECT  15.781 0.096 15.908 6.6 ;
     RECT  14.725 8.352 15.908 8.376 ;
     RECT  15.649 12.336 15.908 19.272 ;
     RECT  15.908 0.096 16.012 19.452 ;
     RECT  16.012 0.096 16.204 19.272 ;
     RECT  16.204 0.096 16.409 6.936 ;
     RECT  16.204 12.336 16.409 19.272 ;
     RECT  16.409 18.72 16.625 19.272 ;
     RECT  16.409 0.24 16.669 6.936 ;
     RECT  16.409 17.424 16.697 17.736 ;
     RECT  16.409 12.336 16.739 16.104 ;
     RECT  16.669 0.24 16.769 6.36 ;
     RECT  16.625 18.72 17.021 18.84 ;
     RECT  16.739 12.336 17.123 13.128 ;
     RECT  16.204 9.024 17.157 9.096 ;
     RECT  16.697 17.424 17.237 17.448 ;
     RECT  17.021 18.816 17.237 18.84 ;
     RECT  16.739 14.112 17.809 16.104 ;
     RECT  17.809 14.112 18.205 16.152 ;
     RECT  16.769 0.24 18.421 6.312 ;
     RECT  18.421 0.144 18.608 6.312 ;
     RECT  17.305 7.392 18.608 7.416 ;
     RECT  17.157 9.072 18.608 9.096 ;
     RECT  17.123 12.336 18.608 12.6 ;
     RECT  18.205 14.112 18.608 16.584 ;
     RECT  18.608 0.144 18.629 19.452 ;
     RECT  18.629 0.096 18.712 19.452 ;
     RECT  18.712 0.096 18.904 19.182 ;
     RECT  18.904 0.096 19.261 6.12 ;
     RECT  19.261 5.568 19.283 6.12 ;
     RECT  19.283 5.952 19.469 6.12 ;
     RECT  18.904 14.112 19.523 16.584 ;
     RECT  19.523 16.032 19.571 16.584 ;
     RECT  19.571 16.08 19.619 16.584 ;
     RECT  19.469 6 19.667 6.12 ;
     RECT  18.904 7.392 19.715 7.416 ;
     RECT  19.667 6 19.763 6.024 ;
     RECT  19.261 0.096 19.793 4.536 ;
     RECT  19.793 1.248 20.003 4.536 ;
     RECT  19.523 14.112 20.003 14.952 ;
     RECT  19.793 0.096 20.045 0.264 ;
     RECT  20.003 2.496 20.051 4.536 ;
     RECT  19.619 16.08 20.051 16.104 ;
     RECT  20.003 1.248 20.081 1.272 ;
     RECT  20.051 2.496 20.099 4.152 ;
     RECT  20.003 14.112 20.099 14.52 ;
     RECT  20.045 0.096 20.117 0.12 ;
     RECT  20.099 2.496 20.147 2.568 ;
     RECT  18.904 12.336 20.147 12.6 ;
     RECT  20.099 4.128 20.195 4.152 ;
     RECT  20.099 14.496 20.195 14.52 ;
     RECT  20.147 2.544 20.243 2.568 ;
     RECT  20.147 12.336 20.243 12.36 ;
    LAYER M5 ;
     RECT  3.792 0.016 4.584 0.131 ;
     RECT  3.984 0.131 4.488 0.227 ;
     RECT  6.864 0.016 19.08 0.709 ;
     RECT  6.864 0.709 19.128 0.805 ;
     RECT  4.176 0.227 4.488 1.139 ;
     RECT  6.864 0.805 19.752 1.861 ;
     RECT  6.816 1.861 19.752 1.909 ;
     RECT  6.816 1.909 19.992 2.053 ;
     RECT  4.272 1.139 4.488 2.137 ;
     RECT  2.4 2.137 2.52 2.151 ;
     RECT  4.272 2.137 5.22 2.151 ;
     RECT  4.272 2.151 5.412 2.197 ;
     RECT  6.576 2.053 19.992 2.197 ;
     RECT  4.272 2.197 19.992 2.485 ;
     RECT  4.272 2.485 20.136 2.533 ;
     RECT  4.272 2.533 20.232 2.915 ;
     RECT  5.1 2.915 20.232 4.501 ;
     RECT  4.704 4.501 20.232 6.467 ;
     RECT  12.96 6.467 20.232 6.899 ;
     RECT  4.704 6.467 11.352 11.317 ;
     RECT  2.4 2.151 2.712 11.365 ;
     RECT  4.704 11.317 11.784 11.701 ;
     RECT  0.144 9.349 0.168 11.795 ;
     RECT  2.4 11.365 3.624 11.845 ;
     RECT  4.704 11.701 12.024 11.845 ;
     RECT  13.056 6.899 20.232 12.371 ;
     RECT  2.4 11.845 12.024 12.563 ;
     RECT  5.1 12.563 12.024 13.091 ;
     RECT  5.1 13.091 11.784 13.283 ;
     RECT  13.056 12.371 20.184 13.715 ;
     RECT  10.224 13.283 11.784 14.243 ;
     RECT  15.792 13.715 20.184 14.291 ;
     RECT  15.9 14.291 20.184 14.531 ;
     RECT  2.4 12.563 3.624 14.915 ;
     RECT  13.104 13.715 14.808 14.915 ;
     RECT  5.1 13.283 9.144 15.205 ;
     RECT  10.368 14.243 11.784 15.205 ;
     RECT  15.9 14.531 20.04 15.443 ;
     RECT  17.472 15.443 20.04 16.115 ;
     RECT  18.144 16.115 19.608 16.163 ;
     RECT  13.104 14.915 14.76 16.261 ;
     RECT  13.056 16.261 14.76 16.453 ;
     RECT  15.9 15.443 16.392 16.453 ;
     RECT  5.1 15.205 11.784 16.501 ;
     RECT  13.056 16.453 16.392 16.501 ;
     RECT  2.4 14.915 3.288 16.549 ;
     RECT  18.6 16.163 19.608 16.595 ;
     RECT  5.1 16.501 16.392 17.075 ;
     RECT  2.16 16.549 4.104 17.077 ;
     RECT  5.1 17.075 14.424 17.077 ;
     RECT  15.504 17.075 16.392 17.123 ;
     RECT  1.968 17.077 14.424 17.171 ;
     RECT  1.968 17.171 11.88 17.509 ;
     RECT  1.872 17.509 11.88 17.557 ;
     RECT  1.776 17.557 11.88 17.605 ;
     RECT  15.744 17.123 16.392 17.699 ;
     RECT  1.68 17.605 11.88 18.805 ;
     RECT  13.008 17.171 14.424 18.805 ;
     RECT  15.744 17.699 16.212 19.283 ;
     RECT  15.9 19.283 16.212 19.449 ;
     RECT  18.6 16.595 18.912 19.449 ;
     RECT  15.9 19.449 16.02 19.463 ;
     RECT  18.6 19.449 18.72 19.463 ;
     RECT  1.68 18.805 14.664 21.584 ;
  END
END hbfd_rly_136_NS_rr
END LIBRARY
